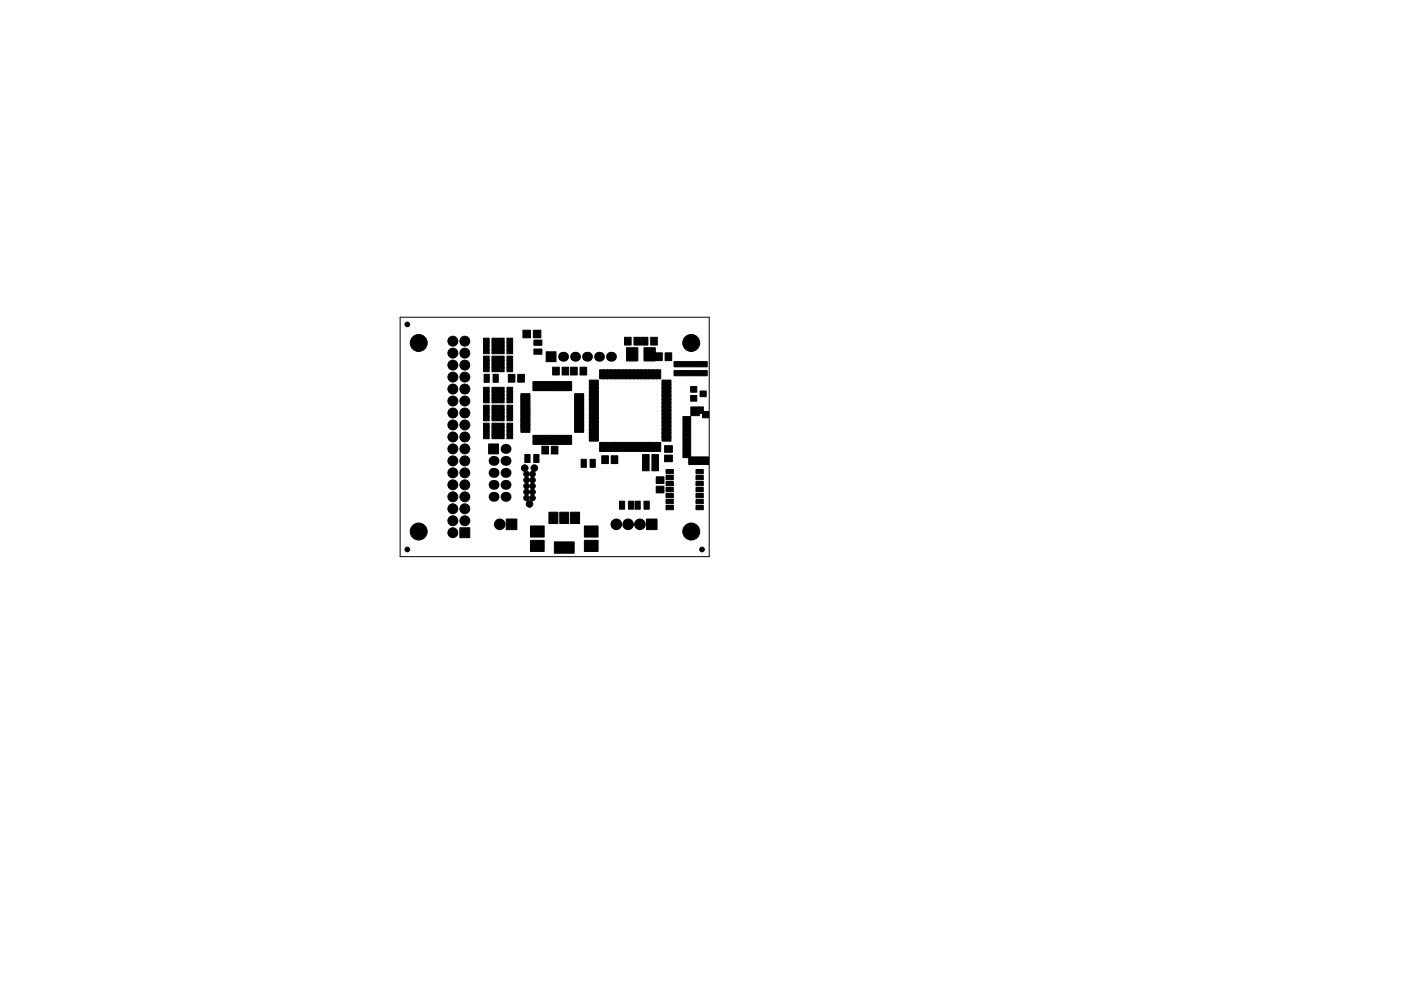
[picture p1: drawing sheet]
<svg xmlns="http://www.w3.org/2000/svg" width="297mm" height="210mm" viewBox="0 0 297 210" stroke-linecap="round" stroke-linejoin="round" font-family="sans-serif">
<path d="M84.8 67.3h65.6v50.8h-65.6z" fill="none" stroke="#000" stroke-width=".21"/>
<g fill="#000" stroke="#000" stroke-width=".21">
<path d="M102.5 75.6h1.2v.9h-1.2zM102.5 77.2h1.2v.8h-1.2zM102.5 76.4h1.2v.8h-1.2zM102.5 78h1.2v.9h-1.2zM102.5 71.8h1.2v.9h-1.2zM102.5 73.4h1.2v.8h-1.2zM102.5 72.6h1.2v.8h-1.2zM102.5 74.2h1.2v.9h-1.2zM102.6 79.4h1.1v1.7h-1.1zM104.3 76.4h1.2v.8h-1.2zM104.3 75.6h1.2v.9h-1.2zM104.3 77.2h1.2v.8h-1.2z"/>
<path d="M104.3 78h1.2v.9h-1.2zM104.3 72.6h1.2v.8h-1.2zM104.3 71.8h1.2v.9h-1.2zM104.3 73.4h1.2v.8h-1.2zM104.3 74.2h1.2v.9h-1.2zM104.5 79.4h1.1v1.7h-1.1zM105.7 77.2h1.2v.8h-1.2zM105.7 78h1.2v.9h-1.2zM105.7 76.4h1.2v.8h-1.2zM105.7 75.6h1.2v.9h-1.2zM105.7 73.4h1.2v.8h-1.2zM105.7 74.2h1.2v.9h-1.2z"/>
<path d="M105.7 72.6h1.2v.8h-1.2zM105.7 71.8h1.2v.9h-1.2zM107.5 78h1.2v.9h-1.2zM107.5 76.4h1.2v.8h-1.2zM107.5 77.2h1.2v.8h-1.2zM107.5 75.6h1.2v.9h-1.2zM107.5 74.2h1.2v.9h-1.2zM107.5 72.6h1.2v.8h-1.2zM107.5 73.4h1.2v.8h-1.2zM107.5 71.8h1.2v.9h-1.2zM110.9 70.1h1.6v1.6h-1.6zM113.1 70.1h1.6v1.6h-1.6z"/>
<path d="M113.2 74.1h1.7v1.1h-1.7zM113.2 72.2h1.7v1.1h-1.7zM117.2 77.9h1.4v1.7h-1.4zM115.8 74.6h2.1v2.1h-2.1zM119.2 77.9h1.4v1.7h-1.4zM121 77.9h1.4v1.7h-1.4zM123 77.9h1.4v1.7h-1.4zM127.1 78.5h1v1.9h-1zM127.9 78.5h1v1.9h-1zM128.7 78.5h1v1.9h-1zM129.5 78.5h1v1.9h-1zM130.3 78.5h1v1.9h-1z"/>
<path d="M131.1 78.5h1v1.9h-1zM131.9 78.5h1v1.9h-1zM132.4 71.6h1.4v1.6h-1.4zM132.7 78.5h1v1.9h-1zM132.8 73.8h2.4v2.8h-2.4zM133.5 78.5h1v1.9h-1zM134.3 78.5h1v1.9h-1zM134.4 71.6h1.4v1.6h-1.4zM135.1 78.5h1v1.9h-1zM135.9 78.5h1v1.9h-1zM136.5 73.8h2.4v2.8h-2.4zM136.7 78.5h1v1.9h-1z"/>
<path d="M136 71.6h1.4v1.6h-1.4zM137.5 78.5h1v1.9h-1zM138.3 78.5h1v1.9h-1zM139.1 78.5h1v1.9h-1zM138 71.6h1.4v1.6h-1.4zM139 74.9h1.4v1.6h-1.4zM141 74.9h1.4v1.6h-1.4zM142.9 76.7h1.7v1.1h-1.7zM142.9 78.6h1.7v1.1h-1.7zM144.7 76.7h1.7v1.1h-1.7zM144.7 78.6h1.7v1.1h-1.7zM146.5 76.7h1.7v1.1h-1.7z"/>
<path d="M146.5 78.6h1.7v1.1h-1.7zM148.2 76.7h1.7v1.1h-1.7zM148.2 78.6h1.7v1.1h-1.7zM102.5 86h1.2v.9h-1.2zM102.5 87.6h1.2v.8h-1.2zM102.5 86.8h1.2v.8h-1.2zM102.5 88.4h1.2v.9h-1.2zM102.5 82.2h1.2v.9h-1.2zM102.5 83.8h1.2v.8h-1.2zM102.5 83h1.2v.8h-1.2zM102.5 84.6h1.2v.9h-1.2zM102.5 89.8h1.2v.9h-1.2z"/>
<path d="M102.5 91.4h1.2v.8h-1.2zM102.5 90.6h1.2v.8h-1.2zM102.5 92.2h1.2v.9h-1.2zM103.6 94.2h2.1v2.1h-2.1zM104.3 86.8h1.2v.8h-1.2zM104.3 86h1.2v.9h-1.2zM104.3 87.6h1.2v.8h-1.2zM104.3 88.4h1.2v.9h-1.2zM104.3 83h1.2v.8h-1.2zM104.3 82.2h1.2v.9h-1.2zM104.3 83.8h1.2v.8h-1.2zM104.3 84.6h1.2v.9h-1.2z"/>
<path d="M104.3 90.6h1.2v.8h-1.2zM104.3 89.8h1.2v.9h-1.2zM104.3 91.4h1.2v.8h-1.2zM104.3 92.2h1.2v.9h-1.2zM105.7 87.6h1.2v.8h-1.2zM105.7 88.4h1.2v.9h-1.2zM105.7 86.8h1.2v.8h-1.2zM105.7 86h1.2v.9h-1.2zM105.7 83.8h1.2v.8h-1.2zM105.7 84.6h1.2v.9h-1.2zM105.7 83h1.2v.8h-1.2zM105.7 82.2h1.2v.9h-1.2z"/>
<path d="M105.7 91.4h1.2v.8h-1.2zM105.7 92.2h1.2v.9h-1.2zM105.7 90.6h1.2v.8h-1.2zM105.7 89.8h1.2v.9h-1.2zM107.8 79.4h1.4v1.7h-1.4zM107.5 88.4h1.2v.9h-1.2zM107.5 86.8h1.2v.8h-1.2zM107.5 87.6h1.2v.8h-1.2zM107.5 86h1.2v.9h-1.2zM107.5 84.6h1.2v.9h-1.2zM107.5 83h1.2v.8h-1.2zM107.5 83.8h1.2v.8h-1.2z"/>
<path d="M107.5 82.2h1.2v.9h-1.2zM107.5 92.2h1.2v.9h-1.2zM107.5 90.6h1.2v.8h-1.2zM107.5 91.4h1.2v.8h-1.2zM107.5 89.8h1.2v.9h-1.2zM109.8 79.4h1.4v1.7h-1.4zM110.4 83.5h1.9v.7h-1.9zM110.4 84h1.9v.7h-1.9zM110.4 84.5h1.9v.7h-1.9zM110.4 85h1.9v.7h-1.9zM110.4 85.5h1.9v.7h-1.9zM110.4 86h1.9v.7h-1.9z"/>
<path d="M110.4 86.5h1.9v.7h-1.9zM110.4 87h1.9v.7h-1.9zM110.4 87.5h1.9v.7h-1.9zM110.4 88h1.9v.7h-1.9zM110.4 88.5h1.9v.7h-1.9zM110.4 89h1.9v.7h-1.9zM110.4 89.5h1.9v.7h-1.9zM110.4 90h1.9v.7h-1.9zM110.4 90.5h1.9v.7h-1.9zM110.4 91h1.9v.7h-1.9zM111.3 96.4h1.1v1.7h-1.1zM113 92.4h.7v1.9h-.7z"/>
<path d="M113 81h.7v1.9h-.7zM113.5 92.4h.7v1.9h-.7zM113.5 81h.7v1.9h-.7zM113.2 96.4h1.1v1.7h-1.1zM114 92.4h.7v1.9h-.7zM114 81h.7v1.9h-.7zM114.5 92.4h.7v1.9h-.7zM114.5 81h.7v1.9h-.7zM115 92.4h.7v1.9h-.7zM115 81h.7v1.9h-.7zM115.5 92.4h.7v1.9h-.7zM115.5 81h.7v1.9h-.7z"/>
<path d="M114.9 94.7h1.4v1.6h-1.4zM116 92.4h.7v1.9h-.7zM116 81h.7v1.9h-.7zM116.5 92.4h.7v1.9h-.7zM116.5 81h.7v1.9h-.7zM117 92.4h.7v1.9h-.7zM117 81h.7v1.9h-.7zM117.5 92.4h.7v1.9h-.7zM117.5 81h.7v1.9h-.7zM116.9 94.7h1.4v1.6h-1.4zM118 92.4h.7v1.9h-.7zM118 81h.7v1.9h-.7z"/>
<path d="M118.5 92.4h.7v1.9h-.7zM118.5 81h.7v1.9h-.7zM119 92.4h.7v1.9h-.7zM119 81h.7v1.9h-.7zM119.5 92.4h.7v1.9h-.7zM119.5 81h.7v1.9h-.7zM120 92.4h.7v1.9h-.7zM120 81h.7v1.9h-.7zM120.5 92.4h.7v1.9h-.7zM120.5 81h.7v1.9h-.7zM121.8 91h1.9v.7h-1.9zM121.8 90.5h1.9v.7h-1.9z"/>
<path d="M121.8 90h1.9v.7h-1.9zM121.8 89.5h1.9v.7h-1.9zM121.8 89h1.9v.7h-1.9zM121.8 88.5h1.9v.7h-1.9zM121.8 88h1.9v.7h-1.9zM121.8 87.5h1.9v.7h-1.9zM121.8 87h1.9v.7h-1.9zM121.8 86.5h1.9v.7h-1.9zM121.8 86h1.9v.7h-1.9zM121.8 85.5h1.9v.7h-1.9zM121.8 85h1.9v.7h-1.9zM121.8 84.5h1.9v.7h-1.9z"/>
<path d="M121.8 84h1.9v.7h-1.9zM121.8 83.5h1.9v.7h-1.9zM123.2 97.4h1.1v1.7h-1.1zM125.1 97.4h1.1v1.7h-1.1zM125 80.6h1.9v1h-1.9zM125 81.4h1.9v1h-1.9zM125 82.2h1.9v1h-1.9zM125 83h1.9v1h-1.9zM125 83.8h1.9v1h-1.9zM125 84.6h1.9v1h-1.9zM125 85.4h1.9v1h-1.9zM125 86.2h1.9v1h-1.9z"/>
<path d="M125 87h1.9v1h-1.9zM125 87.8h1.9v1h-1.9zM125 88.6h1.9v1h-1.9zM125 89.4h1.9v1h-1.9zM125 90.2h1.9v1h-1.9zM125 91h1.9v1h-1.9zM125 91.8h1.9v1h-1.9zM125 92.6h1.9v1h-1.9zM127.1 93.9h1v1.9h-1zM127.6 96.7h1.4v1.7h-1.4zM127.9 93.9h1v1.9h-1zM128.7 93.9h1v1.9h-1z"/>
<path d="M129.5 93.9h1v1.9h-1zM129.6 96.7h1.4v1.7h-1.4zM130.3 93.9h1v1.9h-1zM131.1 93.9h1v1.9h-1zM131.9 93.9h1v1.9h-1zM132.7 93.9h1v1.9h-1zM133.5 93.9h1v1.9h-1zM134.3 93.9h1v1.9h-1zM135.1 93.9h1v1.9h-1zM135.9 93.9h1v1.9h-1zM136.2 96.5h1.4v1.6h-1.4zM136.7 93.9h1v1.9h-1z"/>
<path d="M137.5 93.9h1v1.9h-1zM136.2 98.2h1.4v1.7h-1.4zM138.2 96.5h1.4v1.6h-1.4zM138.3 93.9h1v1.9h-1zM139.1 93.9h1v1.9h-1zM138.2 98.2h1.4v1.7h-1.4zM140.9 94.6h1.7v1.4h-1.7zM140.9 96.6h1.7v1.4h-1.7zM141.2 99.6h1.6v.9h-1.6zM140.4 92.6h1.9v1h-1.9zM140.4 91.8h1.9v1h-1.9zM140.4 91h1.9v1h-1.9z"/>
<path d="M140.4 90.2h1.9v1h-1.9zM140.4 89.4h1.9v1h-1.9zM140.4 88.6h1.9v1h-1.9zM140.4 87.8h1.9v1h-1.9zM140.4 87h1.9v1h-1.9zM140.4 86.2h1.9v1h-1.9zM140.4 85.4h1.9v1h-1.9zM140.4 84.6h1.9v1h-1.9zM140.4 83.8h1.9v1h-1.9zM140.4 83h1.9v1h-1.9zM140.4 82.2h1.9v1h-1.9zM140.4 81.4h1.9v1h-1.9z"/>
<path d="M140.4 80.6h1.9v1h-1.9zM146.4 82h1.3v1.2h-1.3zM146.4 83.9h1.3v1.2h-1.3zM144.8 88.4h1.6v1h-1.6zM144.8 89.5h1.6v1h-1.6zM144.8 90.6h1.6v1h-1.6zM144.8 91.7h1.6v1h-1.6zM144.8 92.8h1.6v1h-1.6zM144.8 93.9h1.6v1h-1.6zM144.8 95h1.6v1h-1.6zM144.8 96.1h1.6v1h-1.6zM147.6 99.6h1.5v.9h-1.5z"/>
<path d="M146.5 86.3h1.8v1.9h-1.8zM148.4 83h1.3v1.2h-1.3zM148.1 86.3h1v1.4h-1zM146 96.9h4.2v1.6h-4.2zM149 87.3h1.2v1.3h-1.2zM97.5 112h2.1v2.1h-2.1zM107.3 110.1h2.3v2.3h-2.3zM112.5 111.6h2.9v2.3h-2.9zM112.5 114.6h2.9v2.4h-2.9zM116.4 108.7h1.9v2.4h-1.9zM117.5 115h4.2v2.4h-4.2zM118.7 108.7h1.9v2.4h-1.9z"/>
<path d="M121 108.7h1.9v2.4h-1.9zM123.9 111.6h2.9v2.3h-2.9zM123.9 114.6h2.9v2.4h-2.9zM131.3 106.3h1.1v1.7h-1.1zM133.2 106.3h1.1v1.7h-1.1zM134.6 106.3h1.1v1.7h-1.1zM136.5 106.3h1.1v1.7h-1.1zM139.1 101.2h1.7v1.4h-1.7zM139.1 103.2h1.7v1.4h-1.7zM137.1 110.1h2.2v2.3h-2.2zM141.2 100.9h1.6v.9h-1.6zM141.2 102.2h1.6v.9h-1.6z"/>
<path d="M141.2 103.4h1.6v.9h-1.6zM141.2 104.7h1.6v.9h-1.6zM141.2 106h1.6v.9h-1.6zM141.2 107.2h1.6v.9h-1.6zM147.6 107.2h1.5v.9h-1.5zM147.6 106h1.5v.9h-1.5zM147.6 103.4h1.5v.9h-1.5zM147.6 102.2h1.5v.9h-1.5zM147.6 100.9h1.5v.9h-1.5zM147.6 104.7h1.5v.9h-1.5z"/>
<circle cx="86.4" cy="68.8" r=".5"/>
<circle cx="88.8" cy="72.8" r="1.8"/>
<circle cx="96" cy="72.4" r="1.05"/>
<circle cx="96" cy="77.5" r="1.05"/>
<circle cx="96" cy="74.9" r="1.05"/>
<circle cx="98.6" cy="77.5" r="1.05"/>
<circle cx="98.6" cy="74.9" r="1.05"/>
<circle cx="98.6" cy="72.4" r="1.05"/>
<circle cx="146.6" cy="72.8" r="1.8"/>
<circle cx="96" cy="95.2" r="1.05"/>
<circle cx="96" cy="92.7" r="1.05"/>
<circle cx="96" cy="82.5" r="1.05"/>
<circle cx="96" cy="87.6" r="1.05"/>
<circle cx="96" cy="90.2" r="1.05"/>
<circle cx="96" cy="85.1" r="1.05"/>
<circle cx="96" cy="97.8" r="1.05"/>
<circle cx="96" cy="80" r="1.05"/>
<circle cx="98.6" cy="82.5" r="1.05"/>
<circle cx="98.6" cy="95.2" r="1.05"/>
<circle cx="98.6" cy="92.7" r="1.05"/>
<circle cx="98.6" cy="80" r="1.05"/>
<circle cx="98.6" cy="87.6" r="1.05"/>
<circle cx="98.6" cy="97.8" r="1.05"/>
<circle cx="98.6" cy="85.1" r="1.05"/>
<circle cx="98.6" cy="90.2" r="1.05"/>
<circle cx="111.3" cy="99.3" r=".7"/>
<circle cx="113.3" cy="99.3" r=".7"/>
<circle cx="86.4" cy="116.6" r=".5"/>
<circle cx="88.8" cy="112.8" r="1.8"/>
<circle cx="96" cy="105.4" r="1.05"/>
<circle cx="96" cy="110.5" r="1.05"/>
<circle cx="96" cy="100.3" r="1.05"/>
<circle cx="96" cy="107.9" r="1.05"/>
<circle cx="96" cy="102.9" r="1.05"/>
<circle cx="96" cy="113" r="1.05"/>
<circle cx="98.6" cy="110.5" r="1.05"/>
<circle cx="98.6" cy="102.9" r="1.05"/>
<circle cx="98.6" cy="105.4" r="1.05"/>
<circle cx="98.6" cy="107.9" r="1.05"/>
<circle cx="98.6" cy="100.3" r="1.05"/>
<circle cx="106" cy="111.2" r="1.12"/>
<circle cx="111.6" cy="100.6" r=".59"/>
<circle cx="111.6" cy="105.7" r=".59"/>
<circle cx="111.6" cy="103.1" r=".59"/>
<circle cx="111.6" cy="104.4" r=".59"/>
<circle cx="111.6" cy="101.8" r=".59"/>
<circle cx="112.3" cy="106.9" r=".7"/>
<circle cx="112.9" cy="104.4" r=".59"/>
<circle cx="112.9" cy="100.6" r=".59"/>
<circle cx="112.9" cy="105.7" r=".59"/>
<circle cx="112.9" cy="103.1" r=".59"/>
<circle cx="112.9" cy="101.8" r=".59"/>
<circle cx="130.7" cy="111.2" r="1.12"/>
<circle cx="133.2" cy="111.2" r="1.12"/>
<circle cx="135.7" cy="111.2" r="1.12"/>
<circle cx="146.6" cy="112.8" r="1.8"/>
<circle cx="148.8" cy="116.6" r=".5"/>
</g>
<g fill="#000">
<circle cx="119.4" cy="75.7" r="1.05"/>
<circle cx="121.9" cy="75.7" r="1.05"/>
<circle cx="124.5" cy="75.7" r="1.05"/>
<circle cx="127" cy="75.7" r="1.05"/>
<circle cx="129.5" cy="75.7" r="1.05"/>
<circle cx="104.6" cy="97.8" r="1.05"/>
<circle cx="107.2" cy="97.8" r="1.05"/>
<circle cx="107.2" cy="95.2" r="1.05"/>
<circle cx="104.6" cy="105.4" r="1.05"/>
<circle cx="104.6" cy="100.3" r="1.05"/>
<circle cx="104.6" cy="102.9" r="1.05"/>
<circle cx="107.2" cy="105.4" r="1.05"/>
<circle cx="107.2" cy="102.9" r="1.05"/>
<circle cx="107.2" cy="100.3" r="1.05"/>
</g>
</svg>
